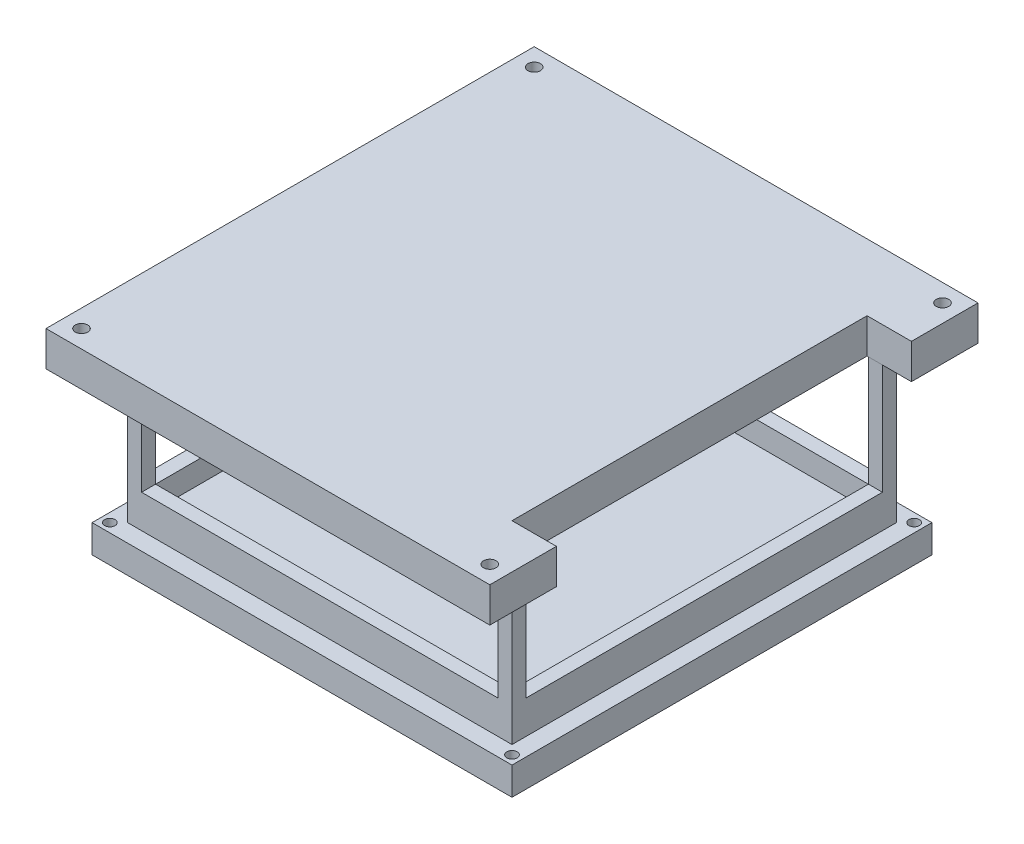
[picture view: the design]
ISO-10303-21;
HEADER;
FILE_DESCRIPTION(('STEP AP214'),'2;1');
FILE_NAME('part.step','',(''),(''),'','','');
FILE_SCHEMA(('AUTOMOTIVE_DESIGN { 1 0 10303 214 1 1 1 1 }'));
ENDSEC;
DATA;
#1=APPLICATION_CONTEXT('core data for automotive mechanical design processes');
#2=APPLICATION_PROTOCOL_DEFINITION('international standard','automotive_design',2000,#1);
#3=PRODUCT_CONTEXT('',#1,'mechanical');
#4=PRODUCT('Part','Part','',(#3));
#5=PRODUCT_RELATED_PRODUCT_CATEGORY('part','',(#4));
#6=PRODUCT_DEFINITION_FORMATION('','',#4);
#7=PRODUCT_DEFINITION_CONTEXT('part definition',#1,'design');
#8=PRODUCT_DEFINITION('design','',#6,#7);
#9=PRODUCT_DEFINITION_SHAPE('','',#8);
#10=(LENGTH_UNIT() NAMED_UNIT(*) SI_UNIT(.MILLI.,.METRE.));
#11=(NAMED_UNIT(*) PLANE_ANGLE_UNIT() SI_UNIT($,.RADIAN.));
#12=(NAMED_UNIT(*) SI_UNIT($,.STERADIAN.) SOLID_ANGLE_UNIT());
#13=UNCERTAINTY_MEASURE_WITH_UNIT(LENGTH_MEASURE(1.E-05),#10,'distance_accuracy_value','');
#14=(GEOMETRIC_REPRESENTATION_CONTEXT(3) GLOBAL_UNCERTAINTY_ASSIGNED_CONTEXT((#13)) GLOBAL_UNIT_ASSIGNED_CONTEXT((#10,
#11,#12)) REPRESENTATION_CONTEXT('',''));
#15=CARTESIAN_POINT('',(0.,0.,0.));
#16=DIRECTION('',(0.,0.,1.));
#17=DIRECTION('',(1.,0.,0.));
#18=AXIS2_PLACEMENT_3D('',#15,#16,#17);
#19=CARTESIAN_POINT('',(63.5,51.275,-69.85));
#20=DIRECTION('',(-1.,0.,0.));
#21=DIRECTION('',(0.,0.,1.));
#22=AXIS2_PLACEMENT_3D('',#19,#20,#21);
#23=PLANE('',#22);
#24=DIRECTION('',(0.,0.,-1.));
#25=VECTOR('',#24,1.);
#26=CARTESIAN_POINT('',(63.5,51.275,-69.85));
#27=LINE('',#26,#25);
#28=CARTESIAN_POINT('',(63.5,51.275,-50.8));
#29=VERTEX_POINT('',#28);
#30=CARTESIAN_POINT('',(63.5,51.275,-69.85));
#31=VERTEX_POINT('',#30);
#32=EDGE_CURVE('E301',#29,#31,#27,.T.);
#33=ORIENTED_EDGE('',*,*,#32,.F.);
#34=DIRECTION('',(0.,1.,0.));
#35=VECTOR('',#34,1.);
#36=CARTESIAN_POINT('',(63.5,41.275,-50.8));
#37=LINE('',#36,#35);
#38=CARTESIAN_POINT('',(63.5,41.275,-50.8));
#39=VERTEX_POINT('',#38);
#40=EDGE_CURVE('E270',#39,#29,#37,.T.);
#41=ORIENTED_EDGE('',*,*,#40,.F.);
#42=DIRECTION('',(0.,0.,-1.));
#43=VECTOR('',#42,1.);
#44=CARTESIAN_POINT('',(63.5,41.275,-69.85));
#45=LINE('',#44,#43);
#46=CARTESIAN_POINT('',(63.5,41.275,-69.85));
#47=VERTEX_POINT('',#46);
#48=EDGE_CURVE('E294',#39,#47,#45,.T.);
#49=ORIENTED_EDGE('',*,*,#48,.T.);
#50=DIRECTION('',(0.,-1.,0.));
#51=VECTOR('',#50,1.);
#52=CARTESIAN_POINT('',(63.5,51.275,-69.85));
#53=LINE('',#52,#51);
#54=EDGE_CURVE('E324',#31,#47,#53,.T.);
#55=ORIENTED_EDGE('',*,*,#54,.F.);
#56=EDGE_LOOP('',(#33,#41,#49,#55));
#57=FACE_BOUND('',#56,.T.);
#58=ADVANCED_FACE('F41',(#57),#23,.F.);
#59=CARTESIAN_POINT('',(0.,9.525,0.));
#60=DIRECTION('',(0.,-1.,0.));
#61=DIRECTION('',(0.,0.,-1.));
#62=AXIS2_PLACEMENT_3D('',#59,#60,#61);
#63=PLANE('',#62);
#64=DIRECTION('',(0.,0.,1.));
#65=VECTOR('',#64,1.);
#66=CARTESIAN_POINT('',(51.,9.525,-55.));
#67=LINE('',#66,#65);
#68=CARTESIAN_POINT('',(51.,9.525,-55.));
#69=VERTEX_POINT('',#68);
#70=CARTESIAN_POINT('',(51.,9.525,-51.));
#71=VERTEX_POINT('',#70);
#72=EDGE_CURVE('E339',#69,#71,#67,.T.);
#73=ORIENTED_EDGE('',*,*,#72,.F.);
#74=DIRECTION('',(-1.,0.,0.));
#75=VECTOR('',#74,1.);
#76=CARTESIAN_POINT('',(-55.,9.525,-55.));
#77=LINE('',#76,#75);
#78=CARTESIAN_POINT('',(-51.,9.525,-55.));
#79=VERTEX_POINT('',#78);
#80=EDGE_CURVE('E526',#69,#79,#77,.T.);
#81=ORIENTED_EDGE('',*,*,#80,.T.);
#82=DIRECTION('',(0.,0.,-1.));
#83=VECTOR('',#82,1.);
#84=CARTESIAN_POINT('',(-51.,9.525,-55.));
#85=LINE('',#84,#83);
#86=CARTESIAN_POINT('',(-51.,9.525,-51.));
#87=VERTEX_POINT('',#86);
#88=EDGE_CURVE('E412',#87,#79,#85,.T.);
#89=ORIENTED_EDGE('',*,*,#88,.F.);
#90=DIRECTION('',(-1.,0.,0.));
#91=VECTOR('',#90,1.);
#92=CARTESIAN_POINT('',(-51.,9.525,-51.));
#93=LINE('',#92,#91);
#94=EDGE_CURVE('E451',#71,#87,#93,.T.);
#95=ORIENTED_EDGE('',*,*,#94,.F.);
#96=EDGE_LOOP('',(#73,#81,#89,#95));
#97=FACE_BOUND('',#96,.T.);
#98=ADVANCED_FACE('F599',(#97),#63,.F.);
#99=DIRECTION('',(1.,0.,0.));
#100=VECTOR('',#99,1.);
#101=CARTESIAN_POINT('',(55.,9.525,-51.));
#102=LINE('',#101,#100);
#103=CARTESIAN_POINT('',(55.,9.525,-51.));
#104=VERTEX_POINT('',#103);
#105=EDGE_CURVE('E337',#71,#104,#102,.T.);
#106=ORIENTED_EDGE('',*,*,#105,.F.);
#107=DIRECTION('',(0.,0.,-1.));
#108=VECTOR('',#107,1.);
#109=CARTESIAN_POINT('',(51.,9.525,51.));
#110=LINE('',#109,#108);
#111=CARTESIAN_POINT('',(51.,9.525,51.));
#112=VERTEX_POINT('',#111);
#113=EDGE_CURVE('E434',#112,#71,#110,.T.);
#114=ORIENTED_EDGE('',*,*,#113,.F.);
#115=DIRECTION('',(-1.,0.,0.));
#116=VECTOR('',#115,1.);
#117=CARTESIAN_POINT('',(55.,9.525,51.));
#118=LINE('',#117,#116);
#119=CARTESIAN_POINT('',(55.,9.525,51.));
#120=VERTEX_POINT('',#119);
#121=EDGE_CURVE('E366',#120,#112,#118,.T.);
#122=ORIENTED_EDGE('',*,*,#121,.F.);
#123=DIRECTION('',(0.,0.,-1.));
#124=VECTOR('',#123,1.);
#125=CARTESIAN_POINT('',(55.,9.525,55.));
#126=LINE('',#125,#124);
#127=EDGE_CURVE('E64',#120,#104,#126,.T.);
#128=ORIENTED_EDGE('',*,*,#127,.T.);
#129=EDGE_LOOP('',(#106,#114,#122,#128));
#130=FACE_BOUND('',#129,.T.);
#131=ADVANCED_FACE('F582',(#130),#63,.F.);
#132=DIRECTION('',(0.,0.,1.));
#133=VECTOR('',#132,1.);
#134=CARTESIAN_POINT('',(51.,9.525,55.));
#135=LINE('',#134,#133);
#136=CARTESIAN_POINT('',(51.,9.525,55.));
#137=VERTEX_POINT('',#136);
#138=EDGE_CURVE('E363',#112,#137,#135,.T.);
#139=ORIENTED_EDGE('',*,*,#138,.F.);
#140=DIRECTION('',(1.,0.,0.));
#141=VECTOR('',#140,1.);
#142=CARTESIAN_POINT('',(-51.,9.525,51.));
#143=LINE('',#142,#141);
#144=CARTESIAN_POINT('',(-51.,9.525,51.));
#145=VERTEX_POINT('',#144);
#146=EDGE_CURVE('E439',#145,#112,#143,.T.);
#147=ORIENTED_EDGE('',*,*,#146,.F.);
#148=DIRECTION('',(0.,0.,-1.));
#149=VECTOR('',#148,1.);
#150=CARTESIAN_POINT('',(-51.,9.525,55.));
#151=LINE('',#150,#149);
#152=CARTESIAN_POINT('',(-51.,9.525,55.));
#153=VERTEX_POINT('',#152);
#154=EDGE_CURVE('E393',#153,#145,#151,.T.);
#155=ORIENTED_EDGE('',*,*,#154,.F.);
#156=DIRECTION('',(1.,0.,0.));
#157=VECTOR('',#156,1.);
#158=CARTESIAN_POINT('',(-55.,9.525,55.));
#159=LINE('',#158,#157);
#160=EDGE_CURVE('E531',#153,#137,#159,.T.);
#161=ORIENTED_EDGE('',*,*,#160,.T.);
#162=EDGE_LOOP('',(#139,#147,#155,#161));
#163=FACE_BOUND('',#162,.T.);
#164=ADVANCED_FACE('F573',(#163),#63,.F.);
#165=DIRECTION('',(-1.,0.,0.));
#166=VECTOR('',#165,1.);
#167=CARTESIAN_POINT('',(-55.,9.525,51.));
#168=LINE('',#167,#166);
#169=CARTESIAN_POINT('',(-55.,9.525,51.));
#170=VERTEX_POINT('',#169);
#171=EDGE_CURVE('E390',#145,#170,#168,.T.);
#172=ORIENTED_EDGE('',*,*,#171,.F.);
#173=DIRECTION('',(0.,0.,1.));
#174=VECTOR('',#173,1.);
#175=CARTESIAN_POINT('',(-51.,9.525,51.));
#176=LINE('',#175,#174);
#177=EDGE_CURVE('E454',#87,#145,#176,.T.);
#178=ORIENTED_EDGE('',*,*,#177,.F.);
#179=DIRECTION('',(1.,0.,0.));
#180=VECTOR('',#179,1.);
#181=CARTESIAN_POINT('',(-55.,9.525,-51.));
#182=LINE('',#181,#180);
#183=CARTESIAN_POINT('',(-55.,9.525,-51.));
#184=VERTEX_POINT('',#183);
#185=EDGE_CURVE('E397',#184,#87,#182,.T.);
#186=ORIENTED_EDGE('',*,*,#185,.F.);
#187=DIRECTION('',(0.,0.,1.));
#188=VECTOR('',#187,1.);
#189=CARTESIAN_POINT('',(-55.,9.525,55.));
#190=LINE('',#189,#188);
#191=EDGE_CURVE('E529',#184,#170,#190,.T.);
#192=ORIENTED_EDGE('',*,*,#191,.T.);
#193=EDGE_LOOP('',(#172,#178,#186,#192));
#194=FACE_BOUND('',#193,.T.);
#195=ADVANCED_FACE('F610',(#194),#63,.F.);
#196=CARTESIAN_POINT('',(55.,9.525,55.));
#197=DIRECTION('',(-1.,0.,0.));
#198=DIRECTION('',(0.,0.,1.));
#199=AXIS2_PLACEMENT_3D('',#196,#197,#198);
#200=PLANE('',#199);
#201=DIRECTION('',(0.,0.,-1.));
#202=VECTOR('',#201,1.);
#203=CARTESIAN_POINT('',(55.,0.,55.));
#204=LINE('',#203,#202);
#205=CARTESIAN_POINT('',(55.,0.,55.));
#206=VERTEX_POINT('',#205);
#207=CARTESIAN_POINT('',(55.,0.,-55.));
#208=VERTEX_POINT('',#207);
#209=EDGE_CURVE('E524',#206,#208,#204,.T.);
#210=ORIENTED_EDGE('',*,*,#209,.T.);
#211=DIRECTION('',(0.,-1.,0.));
#212=VECTOR('',#211,1.);
#213=CARTESIAN_POINT('',(55.,9.525,-55.));
#214=LINE('',#213,#212);
#215=CARTESIAN_POINT('',(55.,41.275,-55.));
#216=VERTEX_POINT('',#215);
#217=EDGE_CURVE('E11',#216,#208,#214,.T.);
#218=ORIENTED_EDGE('',*,*,#217,.F.);
#219=DIRECTION('',(0.,0.,-1.));
#220=VECTOR('',#219,1.);
#221=CARTESIAN_POINT('',(55.,41.275,-55.));
#222=LINE('',#221,#220);
#223=CARTESIAN_POINT('',(55.,41.275,-51.));
#224=VERTEX_POINT('',#223);
#225=EDGE_CURVE('E340',#224,#216,#222,.T.);
#226=ORIENTED_EDGE('',*,*,#225,.F.);
#227=DIRECTION('',(0.,-1.,0.));
#228=VECTOR('',#227,1.);
#229=CARTESIAN_POINT('',(55.,41.275,-51.));
#230=LINE('',#229,#228);
#231=EDGE_CURVE('E333',#224,#104,#230,.T.);
#232=ORIENTED_EDGE('',*,*,#231,.T.);
#233=ORIENTED_EDGE('',*,*,#127,.F.);
#234=DIRECTION('',(0.,-1.,0.));
#235=VECTOR('',#234,1.);
#236=CARTESIAN_POINT('',(55.,41.275,51.));
#237=LINE('',#236,#235);
#238=CARTESIAN_POINT('',(55.,41.275,51.));
#239=VERTEX_POINT('',#238);
#240=EDGE_CURVE('E343',#239,#120,#237,.T.);
#241=ORIENTED_EDGE('',*,*,#240,.F.);
#242=DIRECTION('',(0.,0.,-1.));
#243=VECTOR('',#242,1.);
#244=CARTESIAN_POINT('',(55.,41.275,55.));
#245=LINE('',#244,#243);
#246=CARTESIAN_POINT('',(55.,41.275,55.));
#247=VERTEX_POINT('',#246);
#248=EDGE_CURVE('E376',#247,#239,#245,.T.);
#249=ORIENTED_EDGE('',*,*,#248,.F.);
#250=DIRECTION('',(0.,-1.,0.));
#251=VECTOR('',#250,1.);
#252=CARTESIAN_POINT('',(55.,9.525,55.));
#253=LINE('',#252,#251);
#254=EDGE_CURVE('E533',#247,#206,#253,.T.);
#255=ORIENTED_EDGE('',*,*,#254,.T.);
#256=EDGE_LOOP('',(#210,#218,#226,#232,#233,#241,#249,#255));
#257=FACE_BOUND('',#256,.T.);
#258=ADVANCED_FACE('F43',(#257),#200,.F.);
#259=CARTESIAN_POINT('',(-55.,9.525,-55.));
#260=DIRECTION('',(0.,0.,1.));
#261=DIRECTION('',(1.,0.,0.));
#262=AXIS2_PLACEMENT_3D('',#259,#260,#261);
#263=PLANE('',#262);
#264=DIRECTION('',(-1.,0.,0.));
#265=VECTOR('',#264,1.);
#266=CARTESIAN_POINT('',(-55.,0.,-55.));
#267=LINE('',#266,#265);
#268=CARTESIAN_POINT('',(-55.,0.,-55.));
#269=VERTEX_POINT('',#268);
#270=EDGE_CURVE('E536',#208,#269,#267,.T.);
#271=ORIENTED_EDGE('',*,*,#270,.T.);
#272=DIRECTION('',(0.,-1.,0.));
#273=VECTOR('',#272,1.);
#274=CARTESIAN_POINT('',(-55.,9.525,-55.));
#275=LINE('',#274,#273);
#276=CARTESIAN_POINT('',(-55.,41.275,-55.));
#277=VERTEX_POINT('',#276);
#278=EDGE_CURVE('E49',#277,#269,#275,.T.);
#279=ORIENTED_EDGE('',*,*,#278,.F.);
#280=DIRECTION('',(-1.,0.,0.));
#281=VECTOR('',#280,1.);
#282=CARTESIAN_POINT('',(-55.,41.275,-55.));
#283=LINE('',#282,#281);
#284=CARTESIAN_POINT('',(-51.,41.275,-55.));
#285=VERTEX_POINT('',#284);
#286=EDGE_CURVE('E418',#285,#277,#283,.T.);
#287=ORIENTED_EDGE('',*,*,#286,.F.);
#288=DIRECTION('',(0.,-1.,0.));
#289=VECTOR('',#288,1.);
#290=CARTESIAN_POINT('',(-51.,41.275,-55.));
#291=LINE('',#290,#289);
#292=EDGE_CURVE('E421',#285,#79,#291,.T.);
#293=ORIENTED_EDGE('',*,*,#292,.T.);
#294=ORIENTED_EDGE('',*,*,#80,.F.);
#295=DIRECTION('',(0.,-1.,0.));
#296=VECTOR('',#295,1.);
#297=CARTESIAN_POINT('',(51.,41.275,-55.));
#298=LINE('',#297,#296);
#299=CARTESIAN_POINT('',(51.,41.275,-55.));
#300=VERTEX_POINT('',#299);
#301=EDGE_CURVE('E327',#300,#69,#298,.T.);
#302=ORIENTED_EDGE('',*,*,#301,.F.);
#303=DIRECTION('',(-1.,0.,0.));
#304=VECTOR('',#303,1.);
#305=CARTESIAN_POINT('',(55.,41.275,-55.));
#306=LINE('',#305,#304);
#307=EDGE_CURVE('E349',#216,#300,#306,.T.);
#308=ORIENTED_EDGE('',*,*,#307,.F.);
#309=ORIENTED_EDGE('',*,*,#217,.T.);
#310=EDGE_LOOP('',(#271,#279,#287,#293,#294,#302,#308,#309));
#311=FACE_BOUND('',#310,.T.);
#312=ADVANCED_FACE('F554',(#311),#263,.F.);
#313=CARTESIAN_POINT('',(-55.,9.525,55.));
#314=DIRECTION('',(1.,0.,0.));
#315=DIRECTION('',(0.,0.,-1.));
#316=AXIS2_PLACEMENT_3D('',#313,#314,#315);
#317=PLANE('',#316);
#318=DIRECTION('',(0.,0.,1.));
#319=VECTOR('',#318,1.);
#320=CARTESIAN_POINT('',(-55.,0.,55.));
#321=LINE('',#320,#319);
#322=CARTESIAN_POINT('',(-55.,0.,55.));
#323=VERTEX_POINT('',#322);
#324=EDGE_CURVE('E539',#269,#323,#321,.T.);
#325=ORIENTED_EDGE('',*,*,#324,.T.);
#326=DIRECTION('',(0.,-1.,0.));
#327=VECTOR('',#326,1.);
#328=CARTESIAN_POINT('',(-55.,9.525,55.));
#329=LINE('',#328,#327);
#330=CARTESIAN_POINT('',(-55.,41.275,55.));
#331=VERTEX_POINT('',#330);
#332=EDGE_CURVE('E546',#331,#323,#329,.T.);
#333=ORIENTED_EDGE('',*,*,#332,.F.);
#334=DIRECTION('',(0.,0.,1.));
#335=VECTOR('',#334,1.);
#336=CARTESIAN_POINT('',(-55.,41.275,55.));
#337=LINE('',#336,#335);
#338=CARTESIAN_POINT('',(-55.,41.275,51.));
#339=VERTEX_POINT('',#338);
#340=EDGE_CURVE('E394',#339,#331,#337,.T.);
#341=ORIENTED_EDGE('',*,*,#340,.F.);
#342=DIRECTION('',(0.,-1.,0.));
#343=VECTOR('',#342,1.);
#344=CARTESIAN_POINT('',(-55.,41.275,51.));
#345=LINE('',#344,#343);
#346=EDGE_CURVE('E386',#339,#170,#345,.T.);
#347=ORIENTED_EDGE('',*,*,#346,.T.);
#348=ORIENTED_EDGE('',*,*,#191,.F.);
#349=DIRECTION('',(0.,-1.,0.));
#350=VECTOR('',#349,1.);
#351=CARTESIAN_POINT('',(-55.,41.275,-51.));
#352=LINE('',#351,#350);
#353=CARTESIAN_POINT('',(-55.,41.275,-51.));
#354=VERTEX_POINT('',#353);
#355=EDGE_CURVE('E431',#354,#184,#352,.T.);
#356=ORIENTED_EDGE('',*,*,#355,.F.);
#357=DIRECTION('',(0.,0.,1.));
#358=VECTOR('',#357,1.);
#359=CARTESIAN_POINT('',(-55.,41.275,-55.));
#360=LINE('',#359,#358);
#361=EDGE_CURVE('E408',#277,#354,#360,.T.);
#362=ORIENTED_EDGE('',*,*,#361,.F.);
#363=ORIENTED_EDGE('',*,*,#278,.T.);
#364=EDGE_LOOP('',(#325,#333,#341,#347,#348,#356,#362,#363));
#365=FACE_BOUND('',#364,.T.);
#366=ADVANCED_FACE('F551',(#365),#317,.F.);
#367=CARTESIAN_POINT('',(-55.,9.525,55.));
#368=DIRECTION('',(0.,0.,-1.));
#369=DIRECTION('',(-1.,0.,0.));
#370=AXIS2_PLACEMENT_3D('',#367,#368,#369);
#371=PLANE('',#370);
#372=DIRECTION('',(1.,0.,0.));
#373=VECTOR('',#372,1.);
#374=CARTESIAN_POINT('',(-55.,0.,55.));
#375=LINE('',#374,#373);
#376=EDGE_CURVE('E527',#323,#206,#375,.T.);
#377=ORIENTED_EDGE('',*,*,#376,.T.);
#378=ORIENTED_EDGE('',*,*,#254,.F.);
#379=DIRECTION('',(1.,0.,0.));
#380=VECTOR('',#379,1.);
#381=CARTESIAN_POINT('',(55.,41.275,55.));
#382=LINE('',#381,#380);
#383=CARTESIAN_POINT('',(51.,41.275,55.));
#384=VERTEX_POINT('',#383);
#385=EDGE_CURVE('E367',#384,#247,#382,.T.);
#386=ORIENTED_EDGE('',*,*,#385,.F.);
#387=DIRECTION('',(0.,-1.,0.));
#388=VECTOR('',#387,1.);
#389=CARTESIAN_POINT('',(51.,41.275,55.));
#390=LINE('',#389,#388);
#391=EDGE_CURVE('E359',#384,#137,#390,.T.);
#392=ORIENTED_EDGE('',*,*,#391,.T.);
#393=ORIENTED_EDGE('',*,*,#160,.F.);
#394=DIRECTION('',(0.,-1.,0.));
#395=VECTOR('',#394,1.);
#396=CARTESIAN_POINT('',(-51.,41.275,55.));
#397=LINE('',#396,#395);
#398=CARTESIAN_POINT('',(-51.,41.275,55.));
#399=VERTEX_POINT('',#398);
#400=EDGE_CURVE('E370',#399,#153,#397,.T.);
#401=ORIENTED_EDGE('',*,*,#400,.F.);
#402=DIRECTION('',(1.,0.,0.));
#403=VECTOR('',#402,1.);
#404=CARTESIAN_POINT('',(-55.,41.275,55.));
#405=LINE('',#404,#403);
#406=EDGE_CURVE('E403',#331,#399,#405,.T.);
#407=ORIENTED_EDGE('',*,*,#406,.F.);
#408=ORIENTED_EDGE('',*,*,#332,.T.);
#409=EDGE_LOOP('',(#377,#378,#386,#392,#393,#401,#407,#408));
#410=FACE_BOUND('',#409,.T.);
#411=ADVANCED_FACE('F560',(#410),#371,.F.);
#412=CARTESIAN_POINT('',(0.,0.,0.));
#413=DIRECTION('',(0.,1.,0.));
#414=DIRECTION('',(0.,0.,1.));
#415=AXIS2_PLACEMENT_3D('',#412,#413,#414);
#416=PLANE('',#415);
#417=CARTESIAN_POINT('',(-57.54,0.,57.54));
#418=DIRECTION('',(0.,1.,0.));
#419=DIRECTION('',(0.,0.,-1.));
#420=AXIS2_PLACEMENT_3D('',#417,#418,#419);
#421=CIRCLE('',#420,1.5);
#422=CARTESIAN_POINT('',(-57.54,0.,56.04));
#423=VERTEX_POINT('',#422);
#424=EDGE_CURVE('E484',#423,#423,#421,.T.);
#425=ORIENTED_EDGE('',*,*,#424,.F.);
#426=EDGE_LOOP('',(#425));
#427=FACE_BOUND('',#426,.T.);
#428=CARTESIAN_POINT('',(57.54,0.,57.54));
#429=DIRECTION('',(0.,1.,0.));
#430=DIRECTION('',(0.,0.,1.));
#431=AXIS2_PLACEMENT_3D('',#428,#429,#430);
#432=CIRCLE('',#431,1.5);
#433=CARTESIAN_POINT('',(57.54,0.,59.04));
#434=VERTEX_POINT('',#433);
#435=EDGE_CURVE('E478',#434,#434,#432,.T.);
#436=ORIENTED_EDGE('',*,*,#435,.F.);
#437=EDGE_LOOP('',(#436));
#438=FACE_BOUND('',#437,.T.);
#439=CARTESIAN_POINT('',(57.54,0.,-57.54));
#440=DIRECTION('',(0.,1.,0.));
#441=DIRECTION('',(0.,0.,-1.));
#442=AXIS2_PLACEMENT_3D('',#439,#440,#441);
#443=CIRCLE('',#442,1.5);
#444=CARTESIAN_POINT('',(57.54,0.,-59.04));
#445=VERTEX_POINT('',#444);
#446=EDGE_CURVE('E471',#445,#445,#443,.T.);
#447=ORIENTED_EDGE('',*,*,#446,.F.);
#448=EDGE_LOOP('',(#447));
#449=FACE_BOUND('',#448,.T.);
#450=CARTESIAN_POINT('',(-57.54,0.,-57.54));
#451=DIRECTION('',(0.,1.,0.));
#452=DIRECTION('',(0.,0.,1.));
#453=AXIS2_PLACEMENT_3D('',#450,#451,#452);
#454=CIRCLE('',#453,1.5);
#455=CARTESIAN_POINT('',(-57.54,0.,-56.04));
#456=VERTEX_POINT('',#455);
#457=EDGE_CURVE('E474',#456,#456,#454,.T.);
#458=ORIENTED_EDGE('',*,*,#457,.F.);
#459=EDGE_LOOP('',(#458));
#460=FACE_BOUND('',#459,.T.);
#461=DIRECTION('',(0.,0.,1.));
#462=VECTOR('',#461,1.);
#463=CARTESIAN_POINT('',(60.08,0.,-60.08));
#464=LINE('',#463,#462);
#465=CARTESIAN_POINT('',(60.08,0.,-60.08));
#466=VERTEX_POINT('',#465);
#467=CARTESIAN_POINT('',(60.08,0.,60.08));
#468=VERTEX_POINT('',#467);
#469=EDGE_CURVE('E492',#466,#468,#464,.T.);
#470=ORIENTED_EDGE('',*,*,#469,.F.);
#471=DIRECTION('',(1.,0.,0.));
#472=VECTOR('',#471,1.);
#473=CARTESIAN_POINT('',(-60.08,0.,-60.08));
#474=LINE('',#473,#472);
#475=CARTESIAN_POINT('',(-60.08,0.,-60.08));
#476=VERTEX_POINT('',#475);
#477=EDGE_CURVE('E499',#476,#466,#474,.T.);
#478=ORIENTED_EDGE('',*,*,#477,.F.);
#479=DIRECTION('',(0.,0.,-1.));
#480=VECTOR('',#479,1.);
#481=CARTESIAN_POINT('',(-60.08,0.,-60.08));
#482=LINE('',#481,#480);
#483=CARTESIAN_POINT('',(-60.08,0.,60.08));
#484=VERTEX_POINT('',#483);
#485=EDGE_CURVE('E510',#484,#476,#482,.T.);
#486=ORIENTED_EDGE('',*,*,#485,.F.);
#487=DIRECTION('',(-1.,0.,0.));
#488=VECTOR('',#487,1.);
#489=CARTESIAN_POINT('',(-60.08,0.,60.08));
#490=LINE('',#489,#488);
#491=EDGE_CURVE('E508',#468,#484,#490,.T.);
#492=ORIENTED_EDGE('',*,*,#491,.F.);
#493=EDGE_LOOP('',(#470,#478,#486,#492));
#494=FACE_BOUND('',#493,.T.);
#495=ORIENTED_EDGE('',*,*,#209,.F.);
#496=ORIENTED_EDGE('',*,*,#376,.F.);
#497=ORIENTED_EDGE('',*,*,#324,.F.);
#498=ORIENTED_EDGE('',*,*,#270,.F.);
#499=EDGE_LOOP('',(#495,#496,#497,#498));
#500=FACE_BOUND('',#499,.T.);
#501=ADVANCED_FACE('F558',(#427,#438,#449,#460,#494,#500),#416,.T.);
#502=CARTESIAN_POINT('',(60.08,-8.,-60.08));
#503=DIRECTION('',(-1.,0.,0.));
#504=DIRECTION('',(0.,0.,1.));
#505=AXIS2_PLACEMENT_3D('',#502,#503,#504);
#506=PLANE('',#505);
#507=ORIENTED_EDGE('',*,*,#469,.T.);
#508=DIRECTION('',(0.,1.,0.));
#509=VECTOR('',#508,1.);
#510=CARTESIAN_POINT('',(60.08,-8.,60.08));
#511=LINE('',#510,#509);
#512=CARTESIAN_POINT('',(60.08,-8.,60.08));
#513=VERTEX_POINT('',#512);
#514=EDGE_CURVE('E521',#513,#468,#511,.T.);
#515=ORIENTED_EDGE('',*,*,#514,.F.);
#516=DIRECTION('',(0.,0.,1.));
#517=VECTOR('',#516,1.);
#518=CARTESIAN_POINT('',(60.08,-8.,-60.08));
#519=LINE('',#518,#517);
#520=CARTESIAN_POINT('',(60.08,-8.,-60.08));
#521=VERTEX_POINT('',#520);
#522=EDGE_CURVE('E495',#521,#513,#519,.T.);
#523=ORIENTED_EDGE('',*,*,#522,.F.);
#524=DIRECTION('',(0.,1.,0.));
#525=VECTOR('',#524,1.);
#526=CARTESIAN_POINT('',(60.08,-8.,-60.08));
#527=LINE('',#526,#525);
#528=EDGE_CURVE('E505',#521,#466,#527,.T.);
#529=ORIENTED_EDGE('',*,*,#528,.T.);
#530=EDGE_LOOP('',(#507,#515,#523,#529));
#531=FACE_BOUND('',#530,.T.);
#532=ADVANCED_FACE('F961',(#531),#506,.F.);
#533=CARTESIAN_POINT('',(-60.08,-8.,60.08));
#534=DIRECTION('',(0.,0.,-1.));
#535=DIRECTION('',(-1.,0.,0.));
#536=AXIS2_PLACEMENT_3D('',#533,#534,#535);
#537=PLANE('',#536);
#538=ORIENTED_EDGE('',*,*,#491,.T.);
#539=DIRECTION('',(0.,1.,0.));
#540=VECTOR('',#539,1.);
#541=CARTESIAN_POINT('',(-60.08,-8.,60.08));
#542=LINE('',#541,#540);
#543=CARTESIAN_POINT('',(-60.08,-8.,60.08));
#544=VERTEX_POINT('',#543);
#545=EDGE_CURVE('E518',#544,#484,#542,.T.);
#546=ORIENTED_EDGE('',*,*,#545,.F.);
#547=DIRECTION('',(-1.,0.,0.));
#548=VECTOR('',#547,1.);
#549=CARTESIAN_POINT('',(-60.08,-8.,60.08));
#550=LINE('',#549,#548);
#551=EDGE_CURVE('E498',#513,#544,#550,.T.);
#552=ORIENTED_EDGE('',*,*,#551,.F.);
#553=ORIENTED_EDGE('',*,*,#514,.T.);
#554=EDGE_LOOP('',(#538,#546,#552,#553));
#555=FACE_BOUND('',#554,.T.);
#556=ADVANCED_FACE('F952',(#555),#537,.F.);
#557=CARTESIAN_POINT('',(-60.08,-8.,-60.08));
#558=DIRECTION('',(1.,0.,0.));
#559=DIRECTION('',(0.,0.,-1.));
#560=AXIS2_PLACEMENT_3D('',#557,#558,#559);
#561=PLANE('',#560);
#562=ORIENTED_EDGE('',*,*,#485,.T.);
#563=DIRECTION('',(0.,1.,0.));
#564=VECTOR('',#563,1.);
#565=CARTESIAN_POINT('',(-60.08,-8.,-60.08));
#566=LINE('',#565,#564);
#567=CARTESIAN_POINT('',(-60.08,-8.,-60.08));
#568=VERTEX_POINT('',#567);
#569=EDGE_CURVE('E515',#568,#476,#566,.T.);
#570=ORIENTED_EDGE('',*,*,#569,.F.);
#571=DIRECTION('',(0.,0.,-1.));
#572=VECTOR('',#571,1.);
#573=CARTESIAN_POINT('',(-60.08,-8.,-60.08));
#574=LINE('',#573,#572);
#575=EDGE_CURVE('E501',#544,#568,#574,.T.);
#576=ORIENTED_EDGE('',*,*,#575,.F.);
#577=ORIENTED_EDGE('',*,*,#545,.T.);
#578=EDGE_LOOP('',(#562,#570,#576,#577));
#579=FACE_BOUND('',#578,.T.);
#580=ADVANCED_FACE('F943',(#579),#561,.F.);
#581=CARTESIAN_POINT('',(-60.08,-8.,-60.08));
#582=DIRECTION('',(0.,0.,1.));
#583=DIRECTION('',(1.,0.,0.));
#584=AXIS2_PLACEMENT_3D('',#581,#582,#583);
#585=PLANE('',#584);
#586=ORIENTED_EDGE('',*,*,#477,.T.);
#587=ORIENTED_EDGE('',*,*,#528,.F.);
#588=DIRECTION('',(1.,0.,0.));
#589=VECTOR('',#588,1.);
#590=CARTESIAN_POINT('',(-60.08,-8.,-60.08));
#591=LINE('',#590,#589);
#592=EDGE_CURVE('E503',#568,#521,#591,.T.);
#593=ORIENTED_EDGE('',*,*,#592,.F.);
#594=ORIENTED_EDGE('',*,*,#569,.T.);
#595=EDGE_LOOP('',(#586,#587,#593,#594));
#596=FACE_BOUND('',#595,.T.);
#597=ADVANCED_FACE('F934',(#596),#585,.F.);
#598=CARTESIAN_POINT('',(0.,-8.,0.));
#599=DIRECTION('',(0.,1.,0.));
#600=DIRECTION('',(0.,0.,1.));
#601=AXIS2_PLACEMENT_3D('',#598,#599,#600);
#602=PLANE('',#601);
#603=CARTESIAN_POINT('',(-57.54,-8.,57.54));
#604=DIRECTION('',(0.,1.,0.));
#605=DIRECTION('',(0.,0.,-1.));
#606=AXIS2_PLACEMENT_3D('',#603,#604,#605);
#607=CIRCLE('',#606,1.5);
#608=CARTESIAN_POINT('',(-57.54,-8.,56.04));
#609=VERTEX_POINT('',#608);
#610=EDGE_CURVE('E462',#609,#609,#607,.T.);
#611=ORIENTED_EDGE('',*,*,#610,.T.);
#612=EDGE_LOOP('',(#611));
#613=FACE_BOUND('',#612,.T.);
#614=CARTESIAN_POINT('',(57.54,-8.,57.54));
#615=DIRECTION('',(0.,1.,0.));
#616=DIRECTION('',(0.,0.,1.));
#617=AXIS2_PLACEMENT_3D('',#614,#615,#616);
#618=CIRCLE('',#617,1.5);
#619=CARTESIAN_POINT('',(57.54,-8.,59.04));
#620=VERTEX_POINT('',#619);
#621=EDGE_CURVE('E481',#620,#620,#618,.T.);
#622=ORIENTED_EDGE('',*,*,#621,.T.);
#623=EDGE_LOOP('',(#622));
#624=FACE_BOUND('',#623,.T.);
#625=CARTESIAN_POINT('',(57.54,-8.,-57.54));
#626=DIRECTION('',(0.,1.,0.));
#627=DIRECTION('',(0.,0.,-1.));
#628=AXIS2_PLACEMENT_3D('',#625,#626,#627);
#629=CIRCLE('',#628,1.5);
#630=CARTESIAN_POINT('',(57.54,-8.,-59.04));
#631=VERTEX_POINT('',#630);
#632=EDGE_CURVE('E475',#631,#631,#629,.T.);
#633=ORIENTED_EDGE('',*,*,#632,.T.);
#634=EDGE_LOOP('',(#633));
#635=FACE_BOUND('',#634,.T.);
#636=CARTESIAN_POINT('',(-57.54,-8.,-57.54));
#637=DIRECTION('',(0.,1.,0.));
#638=DIRECTION('',(0.,0.,1.));
#639=AXIS2_PLACEMENT_3D('',#636,#637,#638);
#640=CIRCLE('',#639,1.5);
#641=CARTESIAN_POINT('',(-57.54,-8.,-56.04));
#642=VERTEX_POINT('',#641);
#643=EDGE_CURVE('E489',#642,#642,#640,.T.);
#644=ORIENTED_EDGE('',*,*,#643,.T.);
#645=EDGE_LOOP('',(#644));
#646=FACE_BOUND('',#645,.T.);
#647=ORIENTED_EDGE('',*,*,#522,.T.);
#648=ORIENTED_EDGE('',*,*,#551,.T.);
#649=ORIENTED_EDGE('',*,*,#575,.T.);
#650=ORIENTED_EDGE('',*,*,#592,.T.);
#651=EDGE_LOOP('',(#647,#648,#649,#650));
#652=FACE_BOUND('',#651,.T.);
#653=ADVANCED_FACE('F925',(#613,#624,#635,#646,#652),#602,.F.);
#654=CARTESIAN_POINT('',(-57.54,-8.,-57.54));
#655=DIRECTION('',(0.,1.,0.));
#656=DIRECTION('',(0.,0.,1.));
#657=AXIS2_PLACEMENT_3D('',#654,#655,#656);
#658=CYLINDRICAL_SURFACE('',#657,1.5);
#659=ORIENTED_EDGE('',*,*,#643,.F.);
#660=EDGE_LOOP('',(#659));
#661=FACE_BOUND('',#660,.T.);
#662=ORIENTED_EDGE('',*,*,#457,.T.);
#663=EDGE_LOOP('',(#662));
#664=FACE_BOUND('',#663,.T.);
#665=ADVANCED_FACE('F916',(#661,#664),#658,.F.);
#666=CARTESIAN_POINT('',(57.54,-8.,-57.54));
#667=DIRECTION('',(0.,1.,0.));
#668=DIRECTION('',(0.,0.,1.));
#669=AXIS2_PLACEMENT_3D('',#666,#667,#668);
#670=CYLINDRICAL_SURFACE('',#669,1.5);
#671=ORIENTED_EDGE('',*,*,#632,.F.);
#672=EDGE_LOOP('',(#671));
#673=FACE_BOUND('',#672,.T.);
#674=ORIENTED_EDGE('',*,*,#446,.T.);
#675=EDGE_LOOP('',(#674));
#676=FACE_BOUND('',#675,.T.);
#677=ADVANCED_FACE('F907',(#673,#676),#670,.F.);
#678=CARTESIAN_POINT('',(57.54,-8.,57.54));
#679=DIRECTION('',(0.,1.,0.));
#680=DIRECTION('',(0.,0.,1.));
#681=AXIS2_PLACEMENT_3D('',#678,#679,#680);
#682=CYLINDRICAL_SURFACE('',#681,1.5);
#683=ORIENTED_EDGE('',*,*,#621,.F.);
#684=EDGE_LOOP('',(#683));
#685=FACE_BOUND('',#684,.T.);
#686=ORIENTED_EDGE('',*,*,#435,.T.);
#687=EDGE_LOOP('',(#686));
#688=FACE_BOUND('',#687,.T.);
#689=ADVANCED_FACE('F898',(#685,#688),#682,.F.);
#690=CARTESIAN_POINT('',(-57.54,-8.,57.54));
#691=DIRECTION('',(0.,1.,0.));
#692=DIRECTION('',(0.,0.,1.));
#693=AXIS2_PLACEMENT_3D('',#690,#691,#692);
#694=CYLINDRICAL_SURFACE('',#693,1.5);
#695=ORIENTED_EDGE('',*,*,#610,.F.);
#696=EDGE_LOOP('',(#695));
#697=FACE_BOUND('',#696,.T.);
#698=ORIENTED_EDGE('',*,*,#424,.T.);
#699=EDGE_LOOP('',(#698));
#700=FACE_BOUND('',#699,.T.);
#701=ADVANCED_FACE('F890',(#697,#700),#694,.F.);
#702=CARTESIAN_POINT('',(51.,3.175,51.));
#703=DIRECTION('',(1.,0.,0.));
#704=DIRECTION('',(0.,0.,-1.));
#705=AXIS2_PLACEMENT_3D('',#702,#703,#704);
#706=PLANE('',#705);
#707=ORIENTED_EDGE('',*,*,#113,.T.);
#708=DIRECTION('',(0.,1.,0.));
#709=VECTOR('',#708,1.);
#710=CARTESIAN_POINT('',(51.,3.175,-51.));
#711=LINE('',#710,#709);
#712=CARTESIAN_POINT('',(51.,3.175,-51.));
#713=VERTEX_POINT('',#712);
#714=EDGE_CURVE('E448',#713,#71,#711,.T.);
#715=ORIENTED_EDGE('',*,*,#714,.F.);
#716=DIRECTION('',(0.,0.,-1.));
#717=VECTOR('',#716,1.);
#718=CARTESIAN_POINT('',(51.,3.175,51.));
#719=LINE('',#718,#717);
#720=CARTESIAN_POINT('',(51.,3.175,51.));
#721=VERTEX_POINT('',#720);
#722=EDGE_CURVE('E435',#721,#713,#719,.T.);
#723=ORIENTED_EDGE('',*,*,#722,.F.);
#724=DIRECTION('',(0.,1.,0.));
#725=VECTOR('',#724,1.);
#726=CARTESIAN_POINT('',(51.,3.175,51.));
#727=LINE('',#726,#725);
#728=EDGE_CURVE('E459',#721,#112,#727,.T.);
#729=ORIENTED_EDGE('',*,*,#728,.T.);
#730=EDGE_LOOP('',(#707,#715,#723,#729));
#731=FACE_BOUND('',#730,.T.);
#732=ADVANCED_FACE('F577',(#731),#706,.F.);
#733=CARTESIAN_POINT('',(-51.,3.175,51.));
#734=DIRECTION('',(0.,0.,1.));
#735=DIRECTION('',(1.,0.,0.));
#736=AXIS2_PLACEMENT_3D('',#733,#734,#735);
#737=PLANE('',#736);
#738=ORIENTED_EDGE('',*,*,#146,.T.);
#739=ORIENTED_EDGE('',*,*,#728,.F.);
#740=DIRECTION('',(1.,0.,0.));
#741=VECTOR('',#740,1.);
#742=CARTESIAN_POINT('',(-51.,3.175,51.));
#743=LINE('',#742,#741);
#744=CARTESIAN_POINT('',(-51.,3.175,51.));
#745=VERTEX_POINT('',#744);
#746=EDGE_CURVE('E445',#745,#721,#743,.T.);
#747=ORIENTED_EDGE('',*,*,#746,.F.);
#748=DIRECTION('',(0.,1.,0.));
#749=VECTOR('',#748,1.);
#750=CARTESIAN_POINT('',(-51.,3.175,51.));
#751=LINE('',#750,#749);
#752=EDGE_CURVE('E463',#745,#145,#751,.T.);
#753=ORIENTED_EDGE('',*,*,#752,.T.);
#754=EDGE_LOOP('',(#738,#739,#747,#753));
#755=FACE_BOUND('',#754,.T.);
#756=ADVANCED_FACE('F581',(#755),#737,.F.);
#757=CARTESIAN_POINT('',(-51.,3.175,51.));
#758=DIRECTION('',(-1.,0.,0.));
#759=DIRECTION('',(0.,0.,1.));
#760=AXIS2_PLACEMENT_3D('',#757,#758,#759);
#761=PLANE('',#760);
#762=ORIENTED_EDGE('',*,*,#177,.T.);
#763=ORIENTED_EDGE('',*,*,#752,.F.);
#764=DIRECTION('',(0.,0.,1.));
#765=VECTOR('',#764,1.);
#766=CARTESIAN_POINT('',(-51.,3.175,51.));
#767=LINE('',#766,#765);
#768=CARTESIAN_POINT('',(-51.,3.175,-51.));
#769=VERTEX_POINT('',#768);
#770=EDGE_CURVE('E442',#769,#745,#767,.T.);
#771=ORIENTED_EDGE('',*,*,#770,.F.);
#772=DIRECTION('',(0.,1.,0.));
#773=VECTOR('',#772,1.);
#774=CARTESIAN_POINT('',(-51.,3.175,-51.));
#775=LINE('',#774,#773);
#776=EDGE_CURVE('E466',#769,#87,#775,.T.);
#777=ORIENTED_EDGE('',*,*,#776,.T.);
#778=EDGE_LOOP('',(#762,#763,#771,#777));
#779=FACE_BOUND('',#778,.T.);
#780=ADVANCED_FACE('F866',(#779),#761,.F.);
#781=CARTESIAN_POINT('',(-51.,3.175,-51.));
#782=DIRECTION('',(0.,0.,-1.));
#783=DIRECTION('',(-1.,0.,0.));
#784=AXIS2_PLACEMENT_3D('',#781,#782,#783);
#785=PLANE('',#784);
#786=ORIENTED_EDGE('',*,*,#94,.T.);
#787=ORIENTED_EDGE('',*,*,#776,.F.);
#788=DIRECTION('',(-1.,0.,0.));
#789=VECTOR('',#788,1.);
#790=CARTESIAN_POINT('',(-51.,3.175,-51.));
#791=LINE('',#790,#789);
#792=EDGE_CURVE('E438',#713,#769,#791,.T.);
#793=ORIENTED_EDGE('',*,*,#792,.F.);
#794=ORIENTED_EDGE('',*,*,#714,.T.);
#795=EDGE_LOOP('',(#786,#787,#793,#794));
#796=FACE_BOUND('',#795,.T.);
#797=ADVANCED_FACE('F857',(#796),#785,.F.);
#798=CARTESIAN_POINT('',(0.,3.175,0.));
#799=DIRECTION('',(0.,-1.,0.));
#800=DIRECTION('',(0.,0.,-1.));
#801=AXIS2_PLACEMENT_3D('',#798,#799,#800);
#802=PLANE('',#801);
#803=ORIENTED_EDGE('',*,*,#722,.T.);
#804=ORIENTED_EDGE('',*,*,#792,.T.);
#805=ORIENTED_EDGE('',*,*,#770,.T.);
#806=ORIENTED_EDGE('',*,*,#746,.T.);
#807=EDGE_LOOP('',(#803,#804,#805,#806));
#808=FACE_BOUND('',#807,.T.);
#809=ADVANCED_FACE('F821',(#808),#802,.F.);
#810=CARTESIAN_POINT('',(-55.,41.275,-51.));
#811=DIRECTION('',(0.,0.,-1.));
#812=DIRECTION('',(-1.,0.,0.));
#813=AXIS2_PLACEMENT_3D('',#810,#811,#812);
#814=PLANE('',#813);
#815=ORIENTED_EDGE('',*,*,#185,.T.);
#816=DIRECTION('',(0.,-1.,0.));
#817=VECTOR('',#816,1.);
#818=CARTESIAN_POINT('',(-51.,41.275,-51.));
#819=LINE('',#818,#817);
#820=CARTESIAN_POINT('',(-51.,41.275,-51.));
#821=VERTEX_POINT('',#820);
#822=EDGE_CURVE('E428',#821,#87,#819,.T.);
#823=ORIENTED_EDGE('',*,*,#822,.F.);
#824=DIRECTION('',(1.,0.,0.));
#825=VECTOR('',#824,1.);
#826=CARTESIAN_POINT('',(-55.,41.275,-51.));
#827=LINE('',#826,#825);
#828=EDGE_CURVE('E411',#354,#821,#827,.T.);
#829=ORIENTED_EDGE('',*,*,#828,.F.);
#830=ORIENTED_EDGE('',*,*,#355,.T.);
#831=EDGE_LOOP('',(#815,#823,#829,#830));
#832=FACE_BOUND('',#831,.T.);
#833=ADVANCED_FACE('F812',(#832),#814,.F.);
#834=CARTESIAN_POINT('',(-51.,41.275,-55.));
#835=DIRECTION('',(-1.,0.,0.));
#836=DIRECTION('',(0.,0.,1.));
#837=AXIS2_PLACEMENT_3D('',#834,#835,#836);
#838=PLANE('',#837);
#839=ORIENTED_EDGE('',*,*,#88,.T.);
#840=ORIENTED_EDGE('',*,*,#292,.F.);
#841=DIRECTION('',(0.,0.,-1.));
#842=VECTOR('',#841,1.);
#843=CARTESIAN_POINT('',(-51.,41.275,-55.));
#844=LINE('',#843,#842);
#845=EDGE_CURVE('E415',#821,#285,#844,.T.);
#846=ORIENTED_EDGE('',*,*,#845,.F.);
#847=ORIENTED_EDGE('',*,*,#822,.T.);
#848=EDGE_LOOP('',(#839,#840,#846,#847));
#849=FACE_BOUND('',#848,.T.);
#850=ADVANCED_FACE('F803',(#849),#838,.F.);
#851=CARTESIAN_POINT('',(-51.,41.275,55.));
#852=DIRECTION('',(-1.,0.,0.));
#853=DIRECTION('',(0.,0.,1.));
#854=AXIS2_PLACEMENT_3D('',#851,#852,#853);
#855=PLANE('',#854);
#856=ORIENTED_EDGE('',*,*,#154,.T.);
#857=DIRECTION('',(0.,-1.,0.));
#858=VECTOR('',#857,1.);
#859=CARTESIAN_POINT('',(-51.,41.275,51.));
#860=LINE('',#859,#858);
#861=CARTESIAN_POINT('',(-51.,41.275,51.));
#862=VERTEX_POINT('',#861);
#863=EDGE_CURVE('E383',#862,#145,#860,.T.);
#864=ORIENTED_EDGE('',*,*,#863,.F.);
#865=DIRECTION('',(0.,0.,-1.));
#866=VECTOR('',#865,1.);
#867=CARTESIAN_POINT('',(-51.,41.275,55.));
#868=LINE('',#867,#866);
#869=EDGE_CURVE('E400',#399,#862,#868,.T.);
#870=ORIENTED_EDGE('',*,*,#869,.F.);
#871=ORIENTED_EDGE('',*,*,#400,.T.);
#872=EDGE_LOOP('',(#856,#864,#870,#871));
#873=FACE_BOUND('',#872,.T.);
#874=ADVANCED_FACE('F594',(#873),#855,.F.);
#875=CARTESIAN_POINT('',(-55.,41.275,51.));
#876=DIRECTION('',(0.,0.,1.));
#877=DIRECTION('',(1.,0.,0.));
#878=AXIS2_PLACEMENT_3D('',#875,#876,#877);
#879=PLANE('',#878);
#880=ORIENTED_EDGE('',*,*,#171,.T.);
#881=ORIENTED_EDGE('',*,*,#346,.F.);
#882=DIRECTION('',(-1.,0.,0.));
#883=VECTOR('',#882,1.);
#884=CARTESIAN_POINT('',(-55.,41.275,51.));
#885=LINE('',#884,#883);
#886=EDGE_CURVE('E389',#862,#339,#885,.T.);
#887=ORIENTED_EDGE('',*,*,#886,.F.);
#888=ORIENTED_EDGE('',*,*,#863,.T.);
#889=EDGE_LOOP('',(#880,#881,#887,#888));
#890=FACE_BOUND('',#889,.T.);
#891=ADVANCED_FACE('F586',(#890),#879,.F.);
#892=CARTESIAN_POINT('',(55.,41.275,51.));
#893=DIRECTION('',(0.,0.,1.));
#894=DIRECTION('',(1.,0.,0.));
#895=AXIS2_PLACEMENT_3D('',#892,#893,#894);
#896=PLANE('',#895);
#897=ORIENTED_EDGE('',*,*,#121,.T.);
#898=DIRECTION('',(0.,-1.,0.));
#899=VECTOR('',#898,1.);
#900=CARTESIAN_POINT('',(51.,41.275,51.));
#901=LINE('',#900,#899);
#902=CARTESIAN_POINT('',(51.,41.275,51.));
#903=VERTEX_POINT('',#902);
#904=EDGE_CURVE('E356',#903,#112,#901,.T.);
#905=ORIENTED_EDGE('',*,*,#904,.F.);
#906=DIRECTION('',(-1.,0.,0.));
#907=VECTOR('',#906,1.);
#908=CARTESIAN_POINT('',(55.,41.275,51.));
#909=LINE('',#908,#907);
#910=EDGE_CURVE('E373',#239,#903,#909,.T.);
#911=ORIENTED_EDGE('',*,*,#910,.F.);
#912=ORIENTED_EDGE('',*,*,#240,.T.);
#913=EDGE_LOOP('',(#897,#905,#911,#912));
#914=FACE_BOUND('',#913,.T.);
#915=ADVANCED_FACE('F584',(#914),#896,.F.);
#916=CARTESIAN_POINT('',(51.,41.275,55.));
#917=DIRECTION('',(1.,0.,0.));
#918=DIRECTION('',(0.,0.,-1.));
#919=AXIS2_PLACEMENT_3D('',#916,#917,#918);
#920=PLANE('',#919);
#921=ORIENTED_EDGE('',*,*,#138,.T.);
#922=ORIENTED_EDGE('',*,*,#391,.F.);
#923=DIRECTION('',(0.,0.,1.));
#924=VECTOR('',#923,1.);
#925=CARTESIAN_POINT('',(51.,41.275,55.));
#926=LINE('',#925,#924);
#927=EDGE_CURVE('E362',#903,#384,#926,.T.);
#928=ORIENTED_EDGE('',*,*,#927,.F.);
#929=ORIENTED_EDGE('',*,*,#904,.T.);
#930=EDGE_LOOP('',(#921,#922,#928,#929));
#931=FACE_BOUND('',#930,.T.);
#932=ADVANCED_FACE('F570',(#931),#920,.F.);
#933=CARTESIAN_POINT('',(51.,41.275,-55.));
#934=DIRECTION('',(1.,0.,0.));
#935=DIRECTION('',(0.,0.,-1.));
#936=AXIS2_PLACEMENT_3D('',#933,#934,#935);
#937=PLANE('',#936);
#938=ORIENTED_EDGE('',*,*,#72,.T.);
#939=DIRECTION('',(0.,-1.,0.));
#940=VECTOR('',#939,1.);
#941=CARTESIAN_POINT('',(51.,41.275,-51.));
#942=LINE('',#941,#940);
#943=CARTESIAN_POINT('',(51.,41.275,-51.));
#944=VERTEX_POINT('',#943);
#945=EDGE_CURVE('E330',#944,#71,#942,.T.);
#946=ORIENTED_EDGE('',*,*,#945,.F.);
#947=DIRECTION('',(0.,0.,1.));
#948=VECTOR('',#947,1.);
#949=CARTESIAN_POINT('',(51.,41.275,-55.));
#950=LINE('',#949,#948);
#951=EDGE_CURVE('E346',#300,#944,#950,.T.);
#952=ORIENTED_EDGE('',*,*,#951,.F.);
#953=ORIENTED_EDGE('',*,*,#301,.T.);
#954=EDGE_LOOP('',(#938,#946,#952,#953));
#955=FACE_BOUND('',#954,.T.);
#956=ADVANCED_FACE('F592',(#955),#937,.F.);
#957=CARTESIAN_POINT('',(55.,41.275,-51.));
#958=DIRECTION('',(0.,0.,-1.));
#959=DIRECTION('',(-1.,0.,0.));
#960=AXIS2_PLACEMENT_3D('',#957,#958,#959);
#961=PLANE('',#960);
#962=ORIENTED_EDGE('',*,*,#105,.T.);
#963=ORIENTED_EDGE('',*,*,#231,.F.);
#964=DIRECTION('',(1.,0.,0.));
#965=VECTOR('',#964,1.);
#966=CARTESIAN_POINT('',(55.,41.275,-51.));
#967=LINE('',#966,#965);
#968=EDGE_CURVE('E336',#944,#224,#967,.T.);
#969=ORIENTED_EDGE('',*,*,#968,.F.);
#970=ORIENTED_EDGE('',*,*,#945,.T.);
#971=EDGE_LOOP('',(#962,#963,#969,#970));
#972=FACE_BOUND('',#971,.T.);
#973=ADVANCED_FACE('F623',(#972),#961,.F.);
#974=CARTESIAN_POINT('',(0.,41.275,0.));
#975=DIRECTION('',(0.,1.,0.));
#976=DIRECTION('',(0.,0.,1.));
#977=AXIS2_PLACEMENT_3D('',#974,#975,#976);
#978=PLANE('',#977);
#979=CARTESIAN_POINT('',(58.42,41.275,-64.77));
#980=DIRECTION('',(0.,1.,0.));
#981=DIRECTION('',(0.,0.,-1.));
#982=AXIS2_PLACEMENT_3D('',#979,#980,#981);
#983=CIRCLE('',#982,1.778);
#984=CARTESIAN_POINT('',(58.42,41.275,-66.548));
#985=VERTEX_POINT('',#984);
#986=EDGE_CURVE('E279',#985,#985,#983,.T.);
#987=ORIENTED_EDGE('',*,*,#986,.T.);
#988=EDGE_LOOP('',(#987));
#989=FACE_BOUND('',#988,.T.);
#990=CARTESIAN_POINT('',(-58.42,41.275,64.77));
#991=DIRECTION('',(0.,1.,0.));
#992=DIRECTION('',(0.,0.,1.));
#993=AXIS2_PLACEMENT_3D('',#990,#991,#992);
#994=CIRCLE('',#993,1.778);
#995=CARTESIAN_POINT('',(-58.42,41.275,66.548));
#996=VERTEX_POINT('',#995);
#997=EDGE_CURVE('E286',#996,#996,#994,.T.);
#998=ORIENTED_EDGE('',*,*,#997,.T.);
#999=EDGE_LOOP('',(#998));
#1000=FACE_BOUND('',#999,.T.);
#1001=CARTESIAN_POINT('',(58.42,41.275,64.77));
#1002=DIRECTION('',(0.,1.,0.));
#1003=DIRECTION('',(0.,0.,-1.));
#1004=AXIS2_PLACEMENT_3D('',#1001,#1002,#1003);
#1005=CIRCLE('',#1004,1.778);
#1006=CARTESIAN_POINT('',(58.42,41.275,62.992));
#1007=VERTEX_POINT('',#1006);
#1008=EDGE_CURVE('E273',#1007,#1007,#1005,.T.);
#1009=ORIENTED_EDGE('',*,*,#1008,.T.);
#1010=EDGE_LOOP('',(#1009));
#1011=FACE_BOUND('',#1010,.T.);
#1012=CARTESIAN_POINT('',(-58.42,41.275,-64.77));
#1013=DIRECTION('',(0.,1.,0.));
#1014=DIRECTION('',(0.,0.,1.));
#1015=AXIS2_PLACEMENT_3D('',#1012,#1013,#1014);
#1016=CIRCLE('',#1015,1.778);
#1017=CARTESIAN_POINT('',(-58.42,41.275,-62.992));
#1018=VERTEX_POINT('',#1017);
#1019=EDGE_CURVE('E282',#1018,#1018,#1016,.T.);
#1020=ORIENTED_EDGE('',*,*,#1019,.T.);
#1021=EDGE_LOOP('',(#1020));
#1022=FACE_BOUND('',#1021,.T.);
#1023=ORIENTED_EDGE('',*,*,#48,.F.);
#1024=DIRECTION('',(-1.,0.,0.));
#1025=VECTOR('',#1024,1.);
#1026=CARTESIAN_POINT('',(63.5,41.275,-50.8));
#1027=LINE('',#1026,#1025);
#1028=CARTESIAN_POINT('',(50.8,41.275,-50.8));
#1029=VERTEX_POINT('',#1028);
#1030=EDGE_CURVE('E245',#39,#1029,#1027,.T.);
#1031=ORIENTED_EDGE('',*,*,#1030,.T.);
#1032=DIRECTION('',(0.,0.,1.));
#1033=VECTOR('',#1032,1.);
#1034=CARTESIAN_POINT('',(50.8,41.275,-50.8));
#1035=LINE('',#1034,#1033);
#1036=CARTESIAN_POINT('',(50.8,41.275,50.8));
#1037=VERTEX_POINT('',#1036);
#1038=EDGE_CURVE('E240',#1029,#1037,#1035,.T.);
#1039=ORIENTED_EDGE('',*,*,#1038,.T.);
#1040=DIRECTION('',(1.,0.,0.));
#1041=VECTOR('',#1040,1.);
#1042=CARTESIAN_POINT('',(63.5,41.275,50.8));
#1043=LINE('',#1042,#1041);
#1044=CARTESIAN_POINT('',(63.5,41.275,50.8));
#1045=VERTEX_POINT('',#1044);
#1046=EDGE_CURVE('E248',#1037,#1045,#1043,.T.);
#1047=ORIENTED_EDGE('',*,*,#1046,.T.);
#1048=CARTESIAN_POINT('',(63.5,41.275,69.85));
#1049=VERTEX_POINT('',#1048);
#1050=EDGE_CURVE('E308',#1049,#1045,#45,.T.);
#1051=ORIENTED_EDGE('',*,*,#1050,.F.);
#1052=DIRECTION('',(1.,0.,0.));
#1053=VECTOR('',#1052,1.);
#1054=CARTESIAN_POINT('',(-63.5,41.275,69.85));
#1055=LINE('',#1054,#1053);
#1056=CARTESIAN_POINT('',(-63.5,41.275,69.85));
#1057=VERTEX_POINT('',#1056);
#1058=EDGE_CURVE('E314',#1057,#1049,#1055,.T.);
#1059=ORIENTED_EDGE('',*,*,#1058,.F.);
#1060=DIRECTION('',(0.,0.,1.));
#1061=VECTOR('',#1060,1.);
#1062=CARTESIAN_POINT('',(-63.5,41.275,-69.85));
#1063=LINE('',#1062,#1061);
#1064=CARTESIAN_POINT('',(-63.5,41.275,-69.85));
#1065=VERTEX_POINT('',#1064);
#1066=EDGE_CURVE('E312',#1065,#1057,#1063,.T.);
#1067=ORIENTED_EDGE('',*,*,#1066,.F.);
#1068=DIRECTION('',(-1.,0.,0.));
#1069=VECTOR('',#1068,1.);
#1070=CARTESIAN_POINT('',(-63.5,41.275,-69.85));
#1071=LINE('',#1070,#1069);
#1072=EDGE_CURVE('E310',#47,#1065,#1071,.T.);
#1073=ORIENTED_EDGE('',*,*,#1072,.F.);
#1074=EDGE_LOOP('',(#1023,#1031,#1039,#1047,#1051,#1059,#1067,#1073));
#1075=FACE_BOUND('',#1074,.T.);
#1076=ORIENTED_EDGE('',*,*,#968,.T.);
#1077=ORIENTED_EDGE('',*,*,#225,.T.);
#1078=ORIENTED_EDGE('',*,*,#307,.T.);
#1079=ORIENTED_EDGE('',*,*,#951,.T.);
#1080=EDGE_LOOP('',(#1076,#1077,#1078,#1079));
#1081=FACE_BOUND('',#1080,.T.);
#1082=ORIENTED_EDGE('',*,*,#385,.T.);
#1083=ORIENTED_EDGE('',*,*,#248,.T.);
#1084=ORIENTED_EDGE('',*,*,#910,.T.);
#1085=ORIENTED_EDGE('',*,*,#927,.T.);
#1086=EDGE_LOOP('',(#1082,#1083,#1084,#1085));
#1087=FACE_BOUND('',#1086,.T.);
#1088=ORIENTED_EDGE('',*,*,#886,.T.);
#1089=ORIENTED_EDGE('',*,*,#340,.T.);
#1090=ORIENTED_EDGE('',*,*,#406,.T.);
#1091=ORIENTED_EDGE('',*,*,#869,.T.);
#1092=EDGE_LOOP('',(#1088,#1089,#1090,#1091));
#1093=FACE_BOUND('',#1092,.T.);
#1094=ORIENTED_EDGE('',*,*,#845,.T.);
#1095=ORIENTED_EDGE('',*,*,#286,.T.);
#1096=ORIENTED_EDGE('',*,*,#361,.T.);
#1097=ORIENTED_EDGE('',*,*,#828,.T.);
#1098=EDGE_LOOP('',(#1094,#1095,#1096,#1097));
#1099=FACE_BOUND('',#1098,.T.);
#1100=ADVANCED_FACE('F256',(#989,#1000,#1011,#1022,#1075,#1081,#1087,#1093,#1099),#978,.F.);
#1101=ORIENTED_EDGE('',*,*,#1050,.T.);
#1102=DIRECTION('',(0.,1.,0.));
#1103=VECTOR('',#1102,1.);
#1104=CARTESIAN_POINT('',(63.5,41.275,50.8));
#1105=LINE('',#1104,#1103);
#1106=CARTESIAN_POINT('',(63.5,51.275,50.8));
#1107=VERTEX_POINT('',#1106);
#1108=EDGE_CURVE('E244',#1045,#1107,#1105,.T.);
#1109=ORIENTED_EDGE('',*,*,#1108,.T.);
#1110=CARTESIAN_POINT('',(63.5,51.275,69.85));
#1111=VERTEX_POINT('',#1110);
#1112=EDGE_CURVE('E297',#1111,#1107,#27,.T.);
#1113=ORIENTED_EDGE('',*,*,#1112,.F.);
#1114=DIRECTION('',(0.,-1.,0.));
#1115=VECTOR('',#1114,1.);
#1116=CARTESIAN_POINT('',(63.5,51.275,69.85));
#1117=LINE('',#1116,#1115);
#1118=EDGE_CURVE('E307',#1111,#1049,#1117,.T.);
#1119=ORIENTED_EDGE('',*,*,#1118,.T.);
#1120=EDGE_LOOP('',(#1101,#1109,#1113,#1119));
#1121=FACE_BOUND('',#1120,.T.);
#1122=ADVANCED_FACE('F602',(#1121),#23,.F.);
#1123=CARTESIAN_POINT('',(-63.5,51.275,-69.85));
#1124=DIRECTION('',(0.,0.,1.));
#1125=DIRECTION('',(1.,0.,0.));
#1126=AXIS2_PLACEMENT_3D('',#1123,#1124,#1125);
#1127=PLANE('',#1126);
#1128=ORIENTED_EDGE('',*,*,#1072,.T.);
#1129=DIRECTION('',(0.,-1.,0.));
#1130=VECTOR('',#1129,1.);
#1131=CARTESIAN_POINT('',(-63.5,51.275,-69.85));
#1132=LINE('',#1131,#1130);
#1133=CARTESIAN_POINT('',(-63.5,51.275,-69.85));
#1134=VERTEX_POINT('',#1133);
#1135=EDGE_CURVE('E321',#1134,#1065,#1132,.T.);
#1136=ORIENTED_EDGE('',*,*,#1135,.F.);
#1137=DIRECTION('',(-1.,0.,0.));
#1138=VECTOR('',#1137,1.);
#1139=CARTESIAN_POINT('',(-63.5,51.275,-69.85));
#1140=LINE('',#1139,#1138);
#1141=EDGE_CURVE('E300',#31,#1134,#1140,.T.);
#1142=ORIENTED_EDGE('',*,*,#1141,.F.);
#1143=ORIENTED_EDGE('',*,*,#54,.T.);
#1144=EDGE_LOOP('',(#1128,#1136,#1142,#1143));
#1145=FACE_BOUND('',#1144,.T.);
#1146=ADVANCED_FACE('F615',(#1145),#1127,.F.);
#1147=CARTESIAN_POINT('',(-63.5,51.275,-69.85));
#1148=DIRECTION('',(1.,0.,0.));
#1149=DIRECTION('',(0.,0.,-1.));
#1150=AXIS2_PLACEMENT_3D('',#1147,#1148,#1149);
#1151=PLANE('',#1150);
#1152=ORIENTED_EDGE('',*,*,#1066,.T.);
#1153=DIRECTION('',(0.,-1.,0.));
#1154=VECTOR('',#1153,1.);
#1155=CARTESIAN_POINT('',(-63.5,51.275,69.85));
#1156=LINE('',#1155,#1154);
#1157=CARTESIAN_POINT('',(-63.5,51.275,69.85));
#1158=VERTEX_POINT('',#1157);
#1159=EDGE_CURVE('E318',#1158,#1057,#1156,.T.);
#1160=ORIENTED_EDGE('',*,*,#1159,.F.);
#1161=DIRECTION('',(0.,0.,1.));
#1162=VECTOR('',#1161,1.);
#1163=CARTESIAN_POINT('',(-63.5,51.275,-69.85));
#1164=LINE('',#1163,#1162);
#1165=EDGE_CURVE('E303',#1134,#1158,#1164,.T.);
#1166=ORIENTED_EDGE('',*,*,#1165,.F.);
#1167=ORIENTED_EDGE('',*,*,#1135,.T.);
#1168=EDGE_LOOP('',(#1152,#1160,#1166,#1167));
#1169=FACE_BOUND('',#1168,.T.);
#1170=ADVANCED_FACE('F621',(#1169),#1151,.F.);
#1171=CARTESIAN_POINT('',(-63.5,51.275,69.85));
#1172=DIRECTION('',(0.,0.,-1.));
#1173=DIRECTION('',(-1.,0.,0.));
#1174=AXIS2_PLACEMENT_3D('',#1171,#1172,#1173);
#1175=PLANE('',#1174);
#1176=ORIENTED_EDGE('',*,*,#1058,.T.);
#1177=ORIENTED_EDGE('',*,*,#1118,.F.);
#1178=DIRECTION('',(1.,0.,0.));
#1179=VECTOR('',#1178,1.);
#1180=CARTESIAN_POINT('',(-63.5,51.275,69.85));
#1181=LINE('',#1180,#1179);
#1182=EDGE_CURVE('E305',#1158,#1111,#1181,.T.);
#1183=ORIENTED_EDGE('',*,*,#1182,.F.);
#1184=ORIENTED_EDGE('',*,*,#1159,.T.);
#1185=EDGE_LOOP('',(#1176,#1177,#1183,#1184));
#1186=FACE_BOUND('',#1185,.T.);
#1187=ADVANCED_FACE('F632',(#1186),#1175,.F.);
#1188=CARTESIAN_POINT('',(0.,51.275,0.));
#1189=DIRECTION('',(0.,1.,0.));
#1190=DIRECTION('',(0.,0.,1.));
#1191=AXIS2_PLACEMENT_3D('',#1188,#1189,#1190);
#1192=PLANE('',#1191);
#1193=DIRECTION('',(-1.,0.,0.));
#1194=VECTOR('',#1193,1.);
#1195=CARTESIAN_POINT('',(63.5,51.275,-50.8));
#1196=LINE('',#1195,#1194);
#1197=CARTESIAN_POINT('',(50.8,51.275,-50.8));
#1198=VERTEX_POINT('',#1197);
#1199=EDGE_CURVE('E258',#29,#1198,#1196,.T.);
#1200=ORIENTED_EDGE('',*,*,#1199,.F.);
#1201=ORIENTED_EDGE('',*,*,#32,.T.);
#1202=ORIENTED_EDGE('',*,*,#1141,.T.);
#1203=ORIENTED_EDGE('',*,*,#1165,.T.);
#1204=ORIENTED_EDGE('',*,*,#1182,.T.);
#1205=ORIENTED_EDGE('',*,*,#1112,.T.);
#1206=DIRECTION('',(1.,0.,0.));
#1207=VECTOR('',#1206,1.);
#1208=CARTESIAN_POINT('',(63.5,51.275,50.8));
#1209=LINE('',#1208,#1207);
#1210=CARTESIAN_POINT('',(50.8,51.275,50.8));
#1211=VERTEX_POINT('',#1210);
#1212=EDGE_CURVE('E261',#1211,#1107,#1209,.T.);
#1213=ORIENTED_EDGE('',*,*,#1212,.F.);
#1214=DIRECTION('',(0.,0.,1.));
#1215=VECTOR('',#1214,1.);
#1216=CARTESIAN_POINT('',(50.8,51.275,-50.8));
#1217=LINE('',#1216,#1215);
#1218=EDGE_CURVE('E56',#1198,#1211,#1217,.T.);
#1219=ORIENTED_EDGE('',*,*,#1218,.F.);
#1220=EDGE_LOOP('',(#1200,#1201,#1202,#1203,#1204,#1205,#1213,#1219));
#1221=FACE_BOUND('',#1220,.T.);
#1222=CARTESIAN_POINT('',(58.42,51.275,-64.77));
#1223=DIRECTION('',(0.,1.,0.));
#1224=DIRECTION('',(0.,0.,-1.));
#1225=AXIS2_PLACEMENT_3D('',#1222,#1223,#1224);
#1226=CIRCLE('',#1225,1.778);
#1227=CARTESIAN_POINT('',(58.42,51.275,-66.548));
#1228=VERTEX_POINT('',#1227);
#1229=EDGE_CURVE('E283',#1228,#1228,#1226,.T.);
#1230=ORIENTED_EDGE('',*,*,#1229,.F.);
#1231=EDGE_LOOP('',(#1230));
#1232=FACE_BOUND('',#1231,.T.);
#1233=CARTESIAN_POINT('',(-58.42,51.275,64.77));
#1234=DIRECTION('',(0.,1.,0.));
#1235=DIRECTION('',(0.,0.,1.));
#1236=AXIS2_PLACEMENT_3D('',#1233,#1234,#1235);
#1237=CIRCLE('',#1236,1.778);
#1238=CARTESIAN_POINT('',(-58.42,51.275,66.548));
#1239=VERTEX_POINT('',#1238);
#1240=EDGE_CURVE('E276',#1239,#1239,#1237,.T.);
#1241=ORIENTED_EDGE('',*,*,#1240,.F.);
#1242=EDGE_LOOP('',(#1241));
#1243=FACE_BOUND('',#1242,.T.);
#1244=CARTESIAN_POINT('',(58.42,51.275,64.77));
#1245=DIRECTION('',(0.,1.,0.));
#1246=DIRECTION('',(0.,0.,-1.));
#1247=AXIS2_PLACEMENT_3D('',#1244,#1245,#1246);
#1248=CIRCLE('',#1247,1.778);
#1249=CARTESIAN_POINT('',(58.42,51.275,62.992));
#1250=VERTEX_POINT('',#1249);
#1251=EDGE_CURVE('E269',#1250,#1250,#1248,.T.);
#1252=ORIENTED_EDGE('',*,*,#1251,.F.);
#1253=EDGE_LOOP('',(#1252));
#1254=FACE_BOUND('',#1253,.T.);
#1255=CARTESIAN_POINT('',(-58.42,51.275,-64.77));
#1256=DIRECTION('',(0.,1.,0.));
#1257=DIRECTION('',(0.,0.,1.));
#1258=AXIS2_PLACEMENT_3D('',#1255,#1256,#1257);
#1259=CIRCLE('',#1258,1.778);
#1260=CARTESIAN_POINT('',(-58.42,51.275,-62.992));
#1261=VERTEX_POINT('',#1260);
#1262=EDGE_CURVE('E291',#1261,#1261,#1259,.T.);
#1263=ORIENTED_EDGE('',*,*,#1262,.F.);
#1264=EDGE_LOOP('',(#1263));
#1265=FACE_BOUND('',#1264,.T.);
#1266=ADVANCED_FACE('F645',(#1221,#1232,#1243,#1254,#1265),#1192,.T.);
#1267=CARTESIAN_POINT('',(-58.42,51.275,-64.77));
#1268=DIRECTION('',(0.,-1.,0.));
#1269=DIRECTION('',(0.,0.,-1.));
#1270=AXIS2_PLACEMENT_3D('',#1267,#1268,#1269);
#1271=CYLINDRICAL_SURFACE('',#1270,1.778);
#1272=ORIENTED_EDGE('',*,*,#1262,.T.);
#1273=EDGE_LOOP('',(#1272));
#1274=FACE_BOUND('',#1273,.T.);
#1275=ORIENTED_EDGE('',*,*,#1019,.F.);
#1276=EDGE_LOOP('',(#1275));
#1277=FACE_BOUND('',#1276,.T.);
#1278=ADVANCED_FACE('F647',(#1274,#1277),#1271,.F.);
#1279=CARTESIAN_POINT('',(58.42,51.275,64.77));
#1280=DIRECTION('',(0.,-1.,0.));
#1281=DIRECTION('',(0.,0.,-1.));
#1282=AXIS2_PLACEMENT_3D('',#1279,#1280,#1281);
#1283=CYLINDRICAL_SURFACE('',#1282,1.778);
#1284=ORIENTED_EDGE('',*,*,#1251,.T.);
#1285=EDGE_LOOP('',(#1284));
#1286=FACE_BOUND('',#1285,.T.);
#1287=ORIENTED_EDGE('',*,*,#1008,.F.);
#1288=EDGE_LOOP('',(#1287));
#1289=FACE_BOUND('',#1288,.T.);
#1290=ADVANCED_FACE('F659',(#1286,#1289),#1283,.F.);
#1291=CARTESIAN_POINT('',(-58.42,51.275,64.77));
#1292=DIRECTION('',(0.,-1.,0.));
#1293=DIRECTION('',(0.,0.,-1.));
#1294=AXIS2_PLACEMENT_3D('',#1291,#1292,#1293);
#1295=CYLINDRICAL_SURFACE('',#1294,1.778);
#1296=ORIENTED_EDGE('',*,*,#1240,.T.);
#1297=EDGE_LOOP('',(#1296));
#1298=FACE_BOUND('',#1297,.T.);
#1299=ORIENTED_EDGE('',*,*,#997,.F.);
#1300=EDGE_LOOP('',(#1299));
#1301=FACE_BOUND('',#1300,.T.);
#1302=ADVANCED_FACE('F667',(#1298,#1301),#1295,.F.);
#1303=CARTESIAN_POINT('',(58.42,51.275,-64.77));
#1304=DIRECTION('',(0.,-1.,0.));
#1305=DIRECTION('',(0.,0.,-1.));
#1306=AXIS2_PLACEMENT_3D('',#1303,#1304,#1305);
#1307=CYLINDRICAL_SURFACE('',#1306,1.778);
#1308=ORIENTED_EDGE('',*,*,#1229,.T.);
#1309=EDGE_LOOP('',(#1308));
#1310=FACE_BOUND('',#1309,.T.);
#1311=ORIENTED_EDGE('',*,*,#986,.F.);
#1312=EDGE_LOOP('',(#1311));
#1313=FACE_BOUND('',#1312,.T.);
#1314=ADVANCED_FACE('F712',(#1310,#1313),#1307,.F.);
#1315=CARTESIAN_POINT('',(50.8,41.275,-50.8));
#1316=DIRECTION('',(-1.,0.,0.));
#1317=DIRECTION('',(0.,0.,1.));
#1318=AXIS2_PLACEMENT_3D('',#1315,#1316,#1317);
#1319=PLANE('',#1318);
#1320=ORIENTED_EDGE('',*,*,#1218,.T.);
#1321=DIRECTION('',(0.,1.,0.));
#1322=VECTOR('',#1321,1.);
#1323=CARTESIAN_POINT('',(50.8,41.275,50.8));
#1324=LINE('',#1323,#1322);
#1325=EDGE_CURVE('E236',#1037,#1211,#1324,.T.);
#1326=ORIENTED_EDGE('',*,*,#1325,.F.);
#1327=ORIENTED_EDGE('',*,*,#1038,.F.);
#1328=DIRECTION('',(0.,1.,0.));
#1329=VECTOR('',#1328,1.);
#1330=CARTESIAN_POINT('',(50.8,41.275,-50.8));
#1331=LINE('',#1330,#1329);
#1332=EDGE_CURVE('E267',#1029,#1198,#1331,.T.);
#1333=ORIENTED_EDGE('',*,*,#1332,.T.);
#1334=EDGE_LOOP('',(#1320,#1326,#1327,#1333));
#1335=FACE_BOUND('',#1334,.T.);
#1336=ADVANCED_FACE('F238',(#1335),#1319,.F.);
#1337=CARTESIAN_POINT('',(63.5,41.275,-50.8));
#1338=DIRECTION('',(0.,0.,-1.));
#1339=DIRECTION('',(-1.,0.,0.));
#1340=AXIS2_PLACEMENT_3D('',#1337,#1338,#1339);
#1341=PLANE('',#1340);
#1342=ORIENTED_EDGE('',*,*,#1199,.T.);
#1343=ORIENTED_EDGE('',*,*,#1332,.F.);
#1344=ORIENTED_EDGE('',*,*,#1030,.F.);
#1345=ORIENTED_EDGE('',*,*,#40,.T.);
#1346=EDGE_LOOP('',(#1342,#1343,#1344,#1345));
#1347=FACE_BOUND('',#1346,.T.);
#1348=ADVANCED_FACE('F643',(#1347),#1341,.F.);
#1349=CARTESIAN_POINT('',(63.5,41.275,50.8));
#1350=DIRECTION('',(0.,0.,1.));
#1351=DIRECTION('',(1.,0.,0.));
#1352=AXIS2_PLACEMENT_3D('',#1349,#1350,#1351);
#1353=PLANE('',#1352);
#1354=ORIENTED_EDGE('',*,*,#1212,.T.);
#1355=ORIENTED_EDGE('',*,*,#1108,.F.);
#1356=ORIENTED_EDGE('',*,*,#1046,.F.);
#1357=ORIENTED_EDGE('',*,*,#1325,.T.);
#1358=EDGE_LOOP('',(#1354,#1355,#1356,#1357));
#1359=FACE_BOUND('',#1358,.T.);
#1360=ADVANCED_FACE('F249',(#1359),#1353,.F.);
#1361=CLOSED_SHELL('',(#58,#98,#131,#164,#195,#258,#312,#366,#411,#501,#532,#556,#580,#597,#653,
#665,#677,#689,#701,#732,#756,#780,#797,#809,#833,#850,#874,#891,#915,#932,#956,#973,#1100,
#1122,#1146,#1170,#1187,#1266,#1278,#1290,#1302,#1314,#1336,#1348,#1360));
#1362=MANIFOLD_SOLID_BREP('B2',#1361);
#1363=ADVANCED_BREP_SHAPE_REPRESENTATION('',(#18,#1362),#14);
#1364=SHAPE_DEFINITION_REPRESENTATION(#9,#1363);
ENDSEC;
END-ISO-10303-21;
